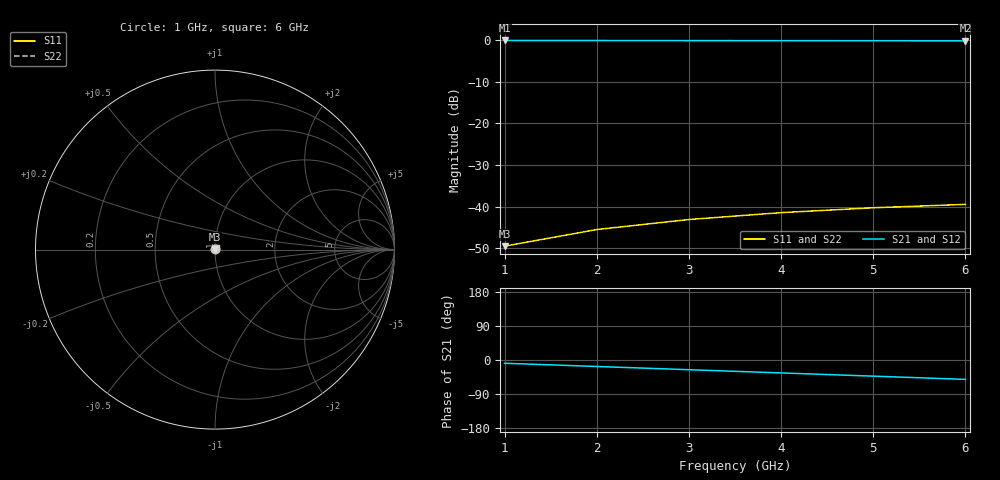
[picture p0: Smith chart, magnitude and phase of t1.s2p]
! Sonnet Data File
! From: em Version : 19.54.2026
! From Project: t1
! Data is De-embedded
! Data File Written: 11/09/2026 22:26:49
!< HDATE 11/09/2026 22:26:47
!< MDATE 11/09/2026 22:26:47
# GHZ S MA R 50.00000
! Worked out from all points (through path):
!   6 points, 1 GHz to 6 GHz, reference 50 ohm
!   highest |S21| = -0.03 dB at 1 GHz (marker M1); lowest = -0.1 dB at 6 GHz (marker M2)
!   lowest |S11| = -49.5 dB at 1 GHz (marker M3), VSWR 1.01, Z = 50.1 + j0.315 ohm
!   |S11| at or under -10 dB: start of sweep to end of sweep
!   |S22| runs from -49.5 to -39.5 dB; largest |S21 - S12| = 0
1  0.003335 70.3  0.9967 -8.6  0.9967 -8.6  0.003335 70.3
2  0.005287 71.0  0.9946 -17.1  0.9946 -17.1  0.005287 71.0
3  0.00698 68.2  0.9926 -25.6  0.9926 -25.6  0.00698 68.2
4  0.008446 63.9  0.9908 -34.1  0.9908 -34.1  0.008446 63.9
5  0.009667 58.7  0.989 -42.6  0.989 -42.6  0.009667 58.7
6  0.01062 53.0  0.9873 -51.1  0.9873 -51.1  0.01062 53.0
